! (c) 2009  Infineon Technologies AG, Munich
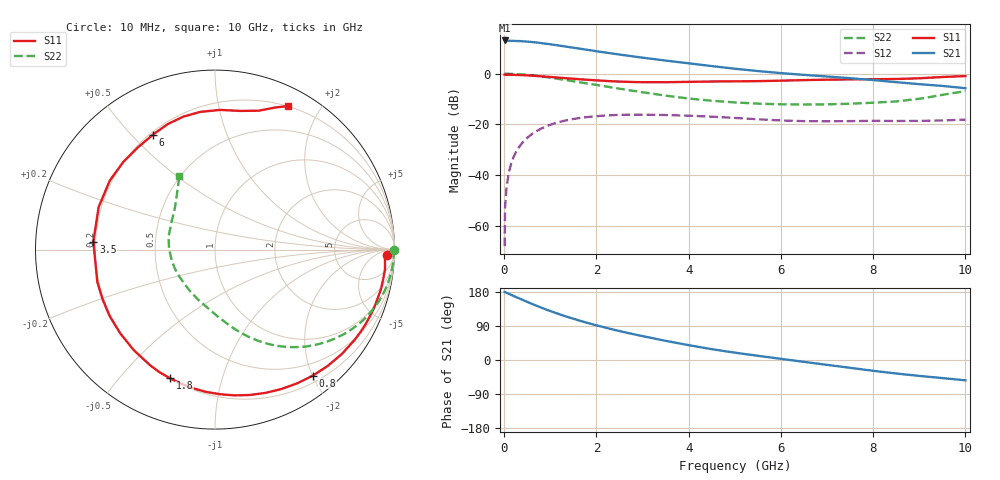
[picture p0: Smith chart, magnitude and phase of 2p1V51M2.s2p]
! Infineon Technologies  Discrete & RF Semiconductors
! BFP420
! VCE =  1.5 V,  IC =  1.2 mA
! Common Emitter S-Parameters:  Nov 2009
# GHz  S  MA  R  50
!  f  S11  S21  S12  S22
! GHz  MAG  ANG  MAG  ANG  MAG  ANG  MAG  ANG
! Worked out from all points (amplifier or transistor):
!   46 points, 10 MHz to 10 GHz, reference 50 ohm
!   highest |S21| = 13.1 dB at 10 MHz (marker M1)
!   |S21| within 3 dB of that: start of sweep to 1.552 GHz
!   unconditionally stable (mu >= 1): 4.264 GHz to end of sweep
!   at 300 MHz: K = 0.03, MSG = 21.2 dB, |S12| = -29.5 dB
!   at 1.7 GHz: K = 0.30, MSG = 13.5 dB, |S12| = -17.3 dB
!   at 10 GHz: K = 1.30, MAG = 2.9 dB, |S12| = -18.1 dB
!   lowest NFmin = 0.53 dB at 900 MHz
!   S11 on the Smith chart (normalised r, x): 10 MHz: 32, -22; 800 MHz: 0.30, -2.01; 1.8 GHz: 0.20, -0.69; 3.5 GHz: 0.19, +0.03; 6 GHz: 0.21, +0.58; 10 GHz: 0.20, +1.61
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0.01  0.9588 -1.7  4.513 179.5  0.0004 97.2  0.9965 -0.1
0.02  0.9509 -1.3  4.372 179.4  0.0023 92.1  0.996 -0.7
0.05  0.9484 -3.2  4.412 177.3  0.0056 87.8  0.9962 -2.0
0.1  0.9537 -6.6  4.436 174.8  0.0111 86.3  0.995 -4.0
0.15  0.9514 -9.9  4.439 172.0  0.0168 84.2  0.9924 -6.0
0.3  0.9442 -19.8  4.395 163.9  0.0334 78.1  0.9788 -11.9
0.5  0.9265 -32.9  4.282 153.4  0.0545 70.1  0.948 -19.5
0.8  0.8888 -52.2  4.003 138.4  0.0826 58.5  0.8832 -30.0
1  0.8602 -64.6  3.793 129.2  0.0985 51.4  0.8337 -36.4
1.2  0.8331 -76.5  3.569 120.6  0.112 44.7  0.7828 -42.2
1.7  0.7694 -104.3  3.052 101.6  0.1364 30.2  0.6633 -54.6
1.8  0.7594 -109.3  2.949 98.1  0.1397 27.5  0.6418 -56.8
2.2  0.7202 -129.0  2.609 85.3  0.15 18.0  0.5609 -64.8
2.6  0.6941 -147.8  2.317 73.6  0.155 9.4  0.4899 -72.2
3  0.6801 -164.6  2.068 63.0  0.1559 2.0  0.4311 -79.1
3.5  0.6793 176.2  1.811 50.6  0.1533 -5.9  0.3699 -88.2
4.5  0.7012 146.7  1.412 28.6  0.1422 -17.4  0.2928 -109.1
5.5  0.7131 127.0  1.126 11.1  0.1265 -23.8  0.2568 -131.0
6  0.7282 118.3  1.027 3.1  0.1198 -24.7  0.2491 -143.0
7  0.7616 103.4  0.879 -12.8  0.1153 -24.4  0.2487 -167.8
8.5  0.7855 79.6  0.68 -35.6  0.1171 -26.6  0.2838 149.5
10  0.8979 63.0  0.517 -53.6  0.1247 -26.4  0.4543 115.9
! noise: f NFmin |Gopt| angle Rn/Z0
0.9  0.53  0.62  33  0.31
1.8  1.1  0.4  77  0.24
2.4  1.23  0.41  100  0.2
3  1.51  0.41  132  0.14
4  1.8  0.44  -175  0.09
5  2.23  0.45  -132  0.38
6  3.18  0.57  -116  0.44
